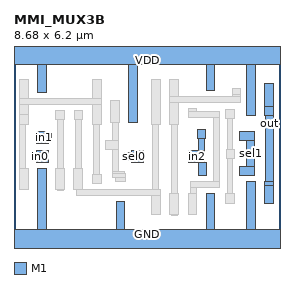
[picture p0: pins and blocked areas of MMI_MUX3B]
MACRO MMI_MUX3B
	CLASS CORE ;
	FOREIGN MMI_MUX3B 0 0 ;
	SIZE 8.68 BY 6.2 ;
	SYMMETRY X Y ;
	SITE CORE1 ;
	PIN out
		DIRECTION output ;
		USE SIGNAL ;
		PORT
			LAYER M1 ;
			RECT 8.19 4.43 8.47 5.175 ;
			LAYER M1 ;
			RECT 8.19 4.115 8.48 4.43 ;
			LAYER M1 ;
			RECT 8.195 1.965 8.48 4.115 ;
			LAYER M1 ;
			RECT 8.19 1.835 8.48 1.965 ;
			LAYER M1 ;
			RECT 8.19 1.265 8.47 1.835 ;
		END
		AntennaDiffArea 0.91245 ;
	END out
	PIN in1
		DIRECTION input ;
		USE SIGNAL ;
		PORT
			LAYER M1 ;
			RECT 0.74 3.55 1.12 3.6 ;
			LAYER M1 ;
			RECT 0.74 3.27 1.23 3.55 ;
			LAYER M1 ;
			RECT 0.74 3.22 1.12 3.27 ;
		END
		AntennaGateArea 0.3465 ;
	END in1
	PIN sel0
		DIRECTION input ;
		USE SIGNAL ;
		PORT
			LAYER M1 ;
			RECT 3.84 2.93 4.22 2.98 ;
			LAYER M1 ;
			RECT 3.595 2.65 4.22 2.93 ;
			LAYER M1 ;
			RECT 3.84 2.6 4.22 2.65 ;
		END
		AntennaGateArea 0.51975 ;
	END sel0
	PIN GND
		DIRECTION inout ;
		USE GROUND ;
		PORT
			LAYER M1 ;
			RECT 0.775 0.42 1.055 2.4 ;
			LAYER M1 ;
			RECT 3.335 0.42 3.62 1.31 ;
			LAYER M1 ;
			RECT 6.27 0.42 6.55 1.585 ;
			LAYER M1 ;
			RECT 7.6 0.42 7.88 1.965 ;
			LAYER M1 ;
			RECT 0 -0.42 8.68 0.42 ;
		END
	END GND
	PIN in2
		DIRECTION input ;
		USE SIGNAL ;
		PORT
			LAYER M1 ;
			RECT 5.975 3.385 6.255 3.665 ;
			LAYER M1 ;
			RECT 6.03 2.975 6.22 3.385 ;
			LAYER M1 ;
			RECT 5.705 2.6 6.22 2.975 ;
			LAYER M1 ;
			RECT 6.005 2.18 6.285 2.6 ;
		END
		AntennaGateArea 0.3465 ;
	END in2
	PIN sel1
		DIRECTION input ;
		USE SIGNAL ;
		PORT
			LAYER M1 ;
			RECT 7.65 3.59 7.845 3.605 ;
			LAYER M1 ;
			RECT 7.37 3.31 7.845 3.59 ;
			LAYER M1 ;
			RECT 7.59 2.45 7.845 3.31 ;
			LAYER M1 ;
			RECT 7.37 2.17 7.845 2.45 ;
			LAYER M1 ;
			RECT 7.65 2.165 7.845 2.17 ;
		END
		AntennaGateArea 0.51975 ;
	END sel1
	PIN VDD
		DIRECTION inout ;
		USE POWER ;
		PORT
			LAYER M1 ;
			RECT 0 5.78 8.68 6.62 ;
			LAYER M1 ;
			RECT 0.775 4.88 1.055 5.78 ;
			LAYER M1 ;
			RECT 3.75 3.915 4.03 5.78 ;
			LAYER M1 ;
			RECT 6.275 4.96 6.555 5.78 ;
			LAYER M1 ;
			RECT 7.6 4.115 7.88 5.78 ;
		END
	END VDD
	PIN in0
		DIRECTION input ;
		USE SIGNAL ;
		PORT
			LAYER M1 ;
			RECT 0.74 2.93 1.12 2.98 ;
			LAYER M1 ;
			RECT 0.58 2.65 1.12 2.93 ;
			LAYER M1 ;
			RECT 0.74 2.6 1.12 2.65 ;
		END
		AntennaGateArea 0.3465 ;
	END in0
	OBS
		LAYER M1 ;
		RECT 0.185 4.675 0.465 5.315 ;
		LAYER M1 ;
		RECT 2.57 4.675 2.85 5.315 ;
		LAYER M1 ;
		RECT 0.185 4.485 2.85 4.675 ;
		LAYER M1 ;
		RECT 0.185 4.145 0.465 4.485 ;
		LAYER M1 ;
		RECT 0.17 3.845 0.465 4.145 ;
		LAYER M1 ;
		RECT 1.365 4 1.645 4.28 ;
		LAYER M1 ;
		RECT 1.965 4 2.245 4.28 ;
		LAYER M1 ;
		RECT 0.17 2.4 0.36 3.845 ;
		LAYER M1 ;
		RECT 1.43 2.4 1.62 4 ;
		LAYER M1 ;
		RECT 2.01 2.4 2.205 4 ;
		LAYER M1 ;
		RECT 2.57 3.845 2.85 4.485 ;
		LAYER M1 ;
		RECT 3.16 3.915 3.44 4.615 ;
		LAYER M1 ;
		RECT 0.17 1.71 0.465 2.4 ;
		LAYER M1 ;
		RECT 0.185 1.7 0.465 1.71 ;
		LAYER M1 ;
		RECT 1.365 1.7 1.645 2.4 ;
		LAYER M1 ;
		RECT 1.955 1.705 2.235 2.4 ;
		LAYER M1 ;
		RECT 2.595 2.195 2.785 3.845 ;
		LAYER M1 ;
		RECT 3.2 3.3 3.395 3.915 ;
		LAYER M1 ;
		RECT 4.5 3.835 4.78 5.305 ;
		LAYER M1 ;
		RECT 5.09 4.745 5.37 5.305 ;
		LAYER M1 ;
		RECT 7.115 4.81 7.395 5 ;
		LAYER M1 ;
		RECT 7.115 4.745 7.4 4.81 ;
		LAYER M1 ;
		RECT 5.09 4.55 7.4 4.745 ;
		LAYER M1 ;
		RECT 5.09 3.835 5.37 4.55 ;
		LAYER M1 ;
		RECT 5.68 4.265 5.96 4.345 ;
		LAYER M1 ;
		RECT 5.68 4.075 6.705 4.265 ;
		LAYER M1 ;
		RECT 5.68 4.065 5.96 4.075 ;
		LAYER M1 ;
		RECT 2.985 3.02 3.395 3.3 ;
		LAYER M1 ;
		RECT 3.2 2.285 3.395 3.02 ;
		LAYER M1 ;
		RECT 3.2 2.24 3.59 2.285 ;
		LAYER M1 ;
		RECT 2.56 1.915 2.84 2.195 ;
		LAYER M1 ;
		RECT 3.2 2.09 3.63 2.24 ;
		LAYER M1 ;
		RECT 3.315 1.96 3.63 2.09 ;
		LAYER M1 ;
		RECT 2.595 1.91 2.785 1.915 ;
		LAYER M1 ;
		RECT 4.53 1.705 4.72 3.835 ;
		LAYER M1 ;
		RECT 1.955 1.7 4.78 1.705 ;
		LAYER M1 ;
		RECT 1.43 1.67 1.62 1.7 ;
		LAYER M1 ;
		RECT 2.045 1.515 4.78 1.7 ;
		LAYER M1 ;
		RECT 5.125 1.585 5.32 3.835 ;
		LAYER M1 ;
		RECT 6.515 1.98 6.705 4.075 ;
		LAYER M1 ;
		RECT 6.91 4.045 7.19 4.325 ;
		LAYER M1 ;
		RECT 6.955 3.02 7.145 4.045 ;
		LAYER M1 ;
		RECT 6.93 2.74 7.21 3.02 ;
		LAYER M1 ;
		RECT 5.76 1.785 6.705 1.98 ;
		LAYER M1 ;
		RECT 5.76 1.585 5.955 1.785 ;
		LAYER M1 ;
		RECT 6.955 1.585 7.145 2.74 ;
		LAYER M1 ;
		RECT 4.5 0.885 4.78 1.515 ;
		LAYER M1 ;
		RECT 5.09 0.885 5.37 1.585 ;
		LAYER M1 ;
		RECT 5.68 0.885 5.96 1.585 ;
		LAYER M1 ;
		RECT 5.125 0.87 5.32 0.885 ;
		LAYER M1 ;
		RECT 6.905 1.27 7.185 1.585 ;
	END
END MMI_MUX3B
